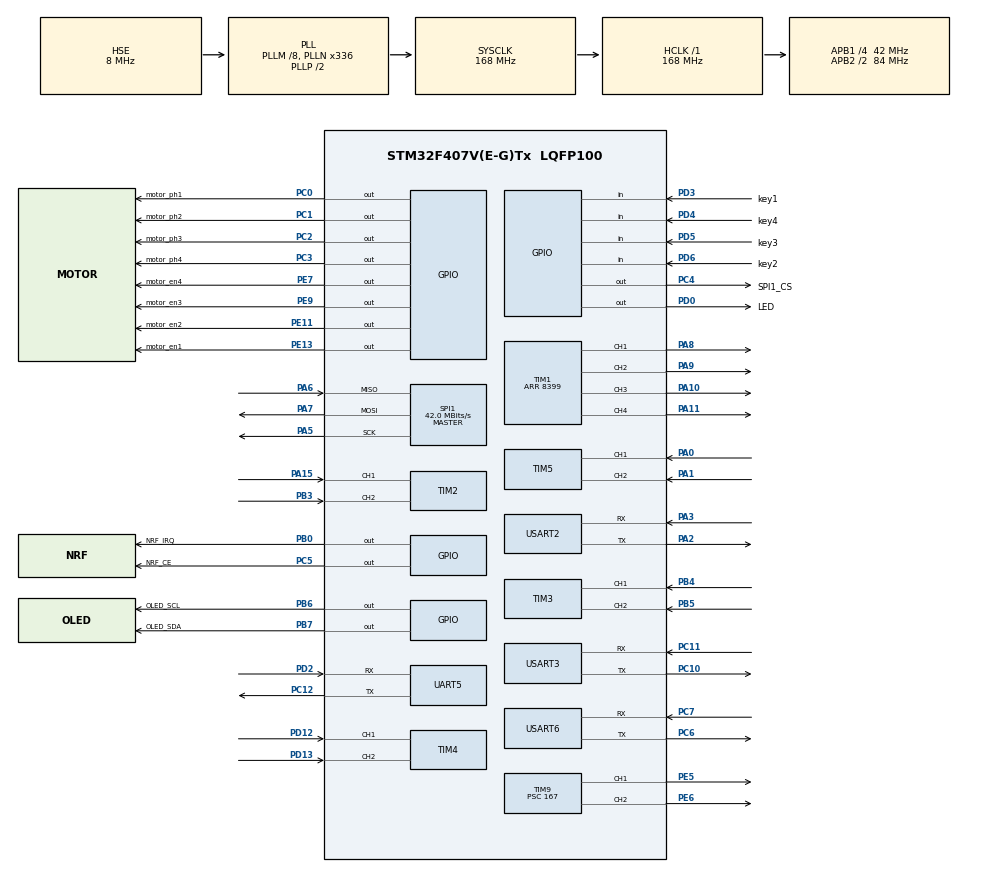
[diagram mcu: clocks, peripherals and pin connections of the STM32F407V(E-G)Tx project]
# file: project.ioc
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Mcu.Family=STM32F4
Mcu.Name=STM32F407V(E-G)Tx
Mcu.Package=LQFP100
NVIC.PriorityGroup=NVIC_PRIORITYGROUP_4
NVIC.UART5_IRQn=true\:0\:0\:false\:false\:true\:true\:true\:true
NVIC.USART2_IRQn=true\:0\:0\:false\:false\:true\:true\:true\:true
NVIC.USART3_IRQn=true\:0\:0\:false\:false\:true\:true\:true\:true
NVIC.USART6_IRQn=true\:0\:0\:false\:false\:true\:true\:true\:true
PA0-WKUP.Signal=S_TIM5_CH1
PA1.Signal=S_TIM5_CH2
PA10.Signal=S_TIM1_CH3
PA11.Signal=S_TIM1_CH4
PA13.Mode=Serial_Wire
PA13.Signal=SYS_JTMS-SWDIO
PA14.Mode=Serial_Wire
PA14.Signal=SYS_JTCK-SWCLK
PA15.Signal=S_TIM2_CH1_ETR
PA2.Mode=Asynchronous
PA2.Signal=USART2_TX
PA3.Mode=Asynchronous
PA3.Signal=USART2_RX
PA5.Mode=Full_Duplex_Master
PA5.Signal=SPI1_SCK
PA6.Mode=Full_Duplex_Master
PA6.Signal=SPI1_MISO
PA7.Mode=Full_Duplex_Master
PA7.Signal=SPI1_MOSI
PA8.Signal=S_TIM1_CH1
PA9.Signal=S_TIM1_CH2
PB0.GPIO_Label=NRF_IRQ
PB0.Signal=GPIO_Output
PB3.Signal=S_TIM2_CH2
PB4.Signal=S_TIM3_CH1
PB5.Signal=S_TIM3_CH2
PB6.GPIO_Label=OLED_SCL
PB6.GPIO_ModeDefaultOutputPP=GPIO_MODE_OUTPUT_PP
PB6.GPIO_PuPd=GPIO_PULLUP
PB6.Signal=GPIO_Output
PB7.GPIO_Label=OLED_SDA
PB7.GPIO_PuPd=GPIO_PULLUP
PB7.PinState=GPIO_PIN_SET
PB7.Signal=GPIO_Output
PC0.GPIO_Label=motor_ph1
PC0.GPIO_Speed=GPIO_SPEED_FREQ_VERY_HIGH
PC0.Signal=GPIO_Output
PC1.GPIO_Label=motor_ph2
PC1.GPIO_Speed=GPIO_SPEED_FREQ_VERY_HIGH
PC1.Signal=GPIO_Output
PC10.Mode=Asynchronous
PC10.Signal=USART3_TX
PC11.Mode=Asynchronous
PC11.Signal=USART3_RX
PC12.Mode=Asynchronous
PC12.Signal=UART5_TX
PC2.GPIO_Label=motor_ph3
PC2.Signal=GPIO_Output
PC3.GPIO_Label=motor_ph4
PC3.Signal=GPIO_Output
PC4.GPIO_Label=SPI1_CS
PC4.Signal=GPIO_Output
PC5.GPIO_Label=NRF_CE
PC5.Signal=GPIO_Output
PC6.Mode=Asynchronous
PC6.Signal=USART6_TX
PC7.Mode=Asynchronous
PC7.Signal=USART6_RX
PD0.GPIO_Label=LED
PD0.Signal=GPIO_Output
PD12.Signal=S_TIM4_CH1
PD13.Signal=S_TIM4_CH2
PD2.Mode=Asynchronous
PD2.Signal=UART5_RX
PD3.GPIO_Label=key1
PD3.Signal=GPIO_Input
PD4.GPIO_Label=key4
PD4.Signal=GPIO_Input
PD5.GPIO_Label=key3
PD5.Signal=GPIO_Input
PD6.GPIO_Label=key2
PD6.Signal=GPIO_Input
PE11.GPIO_Label=motor_en2
PE11.Signal=GPIO_Output
PE13.GPIO_Label=motor_en1
PE13.Signal=GPIO_Output
PE5.Signal=S_TIM9_CH1
PE6.Signal=S_TIM9_CH2
PE7.GPIO_Label=motor_en4
PE7.Signal=GPIO_Output
PE9.GPIO_Label=motor_en3
PE9.Signal=GPIO_Output
PH0-OSC_IN.Mode=HSE-External-Oscillator
PH0-OSC_IN.Signal=RCC_OSC_IN
PH1-OSC_OUT.Mode=HSE-External-Oscillator
PH1-OSC_OUT.Signal=RCC_OSC_OUT
ProjectManager.HeapSize=0x200
ProjectManager.StackSize=0x400
ProjectManager.TargetToolchain=MDK-ARM V5
RCC.48MHZClocksFreq_Value=84000000
RCC.AHBFreq_Value=168000000
RCC.APB1CLKDivider=RCC_HCLK_DIV4
RCC.APB1Freq_Value=42000000
RCC.APB1TimFreq_Value=84000000
RCC.APB2CLKDivider=RCC_HCLK_DIV2
RCC.APB2Freq_Value=84000000
RCC.APB2TimFreq_Value=168000000
RCC.CortexFreq_Value=168000000
RCC.HCLKFreq_Value=168000000
RCC.HSE_VALUE=8000000
RCC.HSI_VALUE=16000000
RCC.LSE_VALUE=32768
RCC.PLLM=8
RCC.PLLN=336
RCC.PLLSourceVirtual=RCC_PLLSOURCE_HSE
RCC.SYSCLKFreq_VALUE=168000000
RCC.SYSCLKSource=RCC_SYSCLKSOURCE_PLLCLK
RCC.VCOOutputFreq_Value=336000000
SH.S_TIM1_CH1.0=TIM1_CH1,PWM Generation1 CH1
SH.S_TIM1_CH2.0=TIM1_CH2,PWM Generation2 CH2
SH.S_TIM1_CH3.0=TIM1_CH3,PWM Generation3 CH3
SH.S_TIM1_CH4.0=TIM1_CH4,PWM Generation4 CH4
SH.S_TIM2_CH1_ETR.0=TIM2_CH1,Encoder_Interface
SH.S_TIM2_CH2.0=TIM2_CH2,Encoder_Interface
SH.S_TIM3_CH1.0=TIM3_CH1,Encoder_Interface
SH.S_TIM3_CH2.0=TIM3_CH2,Encoder_Interface
SH.S_TIM4_CH1.0=TIM4_CH1,Encoder_Interface
SH.S_TIM4_CH2.0=TIM4_CH2,Encoder_Interface
SH.S_TIM5_CH1.0=TIM5_CH1,Encoder_Interface
SH.S_TIM5_CH2.0=TIM5_CH2,Encoder_Interface
SH.S_TIM9_CH1.0=TIM9_CH1,PWM Generation1 CH1
SH.S_TIM9_CH2.0=TIM9_CH2,PWM Generation2 CH2
SPI1.BaudRatePrescaler=SPI_BAUDRATEPRESCALER_2
SPI1.CalculateBaudRate=42.0 MBits/s
SPI1.Direction=SPI_DIRECTION_2LINES
SPI1.Mode=SPI_MODE_MASTER
SPI1.VirtualType=VM_MASTER
TIM1.AutoReloadPreload=TIM_AUTORELOAD_PRELOAD_ENABLE
TIM1.Channel-PWM\ Generation1\ CH1=TIM_CHANNEL_1
TIM1.Channel-PWM\ Generation2\ CH2=TIM_CHANNEL_2
TIM1.Channel-PWM\ Generation3\ CH3=TIM_CHANNEL_3
TIM1.Channel-PWM\ Generation4\ CH4=TIM_CHANNEL_4
TIM1.Period=8399
TIM2.EncoderMode=TIM_ENCODERMODE_TI12
TIM3.EncoderMode=TIM_ENCODERMODE_TI12
TIM4.EncoderMode=TIM_ENCODERMODE_TI12
TIM5.EncoderMode=TIM_ENCODERMODE_TI12
TIM9.Channel-PWM\ Generation1\ CH1=TIM_CHANNEL_1
TIM9.Channel-PWM\ Generation2\ CH2=TIM_CHANNEL_2
TIM9.Period=19999
TIM9.Prescaler=167
UART5.VirtualMode=Asynchronous
USART2.VirtualMode=VM_ASYNC
USART3.VirtualMode=VM_ASYNC
USART6.VirtualMode=VM_ASYNC
VP_TIM1_VS_ClockSourceINT.Mode=Internal
VP_TIM6_VS_ClockSourceINT.Mode=Enable_Timer
VP_TIM9_VS_ClockSourceINT.Mode=Internal
board=custom

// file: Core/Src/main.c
/* USER CODE BEGIN Header */
/**
  ******************************************************************************
  * @file           : main.c
  * @brief          : Main program body
  ******************************************************************************
  * @attention
  *
  * Copyright (c) 2026 STMicroelectronics.
  * All rights reserved.
  *
  * This software is licensed under terms that can be found in the LICENSE file
  * in the root directory of this software component.
  * If no LICENSE file comes with this software, it is provided AS-IS.
  *
  ******************************************************************************
  */
/* USER CODE END Header */
#include "main.h"
#include "scheduler.h"
#include "motor.h"
#include "nrf.h"
#include "led.h"
#include "key.h"
#include "OLED.h"
/* USER CODE BEGIN Includes */
#include "hdz601.h"
#include "encoder.h"
#include "faraway.h"
#include "decode_move.h"
#include "vision_uart6.h"

/* USER CODE END Includes */

SPI_HandleTypeDef hspi1;

TIM_HandleTypeDef htim1;
TIM_HandleTypeDef htim2;
TIM_HandleTypeDef htim3;
TIM_HandleTypeDef htim4;
TIM_HandleTypeDef htim5;
TIM_HandleTypeDef htim6;
TIM_HandleTypeDef htim9;

UART_HandleTypeDef huart5;
UART_HandleTypeDef huart2;
UART_HandleTypeDef huart3;
UART_HandleTypeDef huart6;

void SystemClock_Config(void);
static void MX_GPIO_Init(void);
static void MX_SPI1_Init(void);
static void MX_TIM1_Init(void);
static void MX_TIM2_Init(void);
static void MX_TIM3_Init(void);
static void MX_TIM4_Init(void);
static void MX_TIM5_Init(void);
static void MX_TIM6_Init(void);
static void MX_TIM9_Init(void);
static void MX_UART5_Init(void);
static void MX_USART2_UART_Init(void);
static void MX_USART3_UART_Init(void);
static void MX_USART6_UART_Init(void);

int main(void)
{

    /* MCU Configuration--------------------------------------------------------*/

    /* Reset of all peripherals, Initializes the Flash interface and the Systick. */
    HAL_Init();

    /* Configure the system clock */
    SystemClock_Config();

    /* Initialize all configured peripherals */
    MX_GPIO_Init();
    MX_SPI1_Init();
    MX_TIM1_Init();
    MX_TIM2_Init();
    MX_TIM3_Init();
    MX_TIM4_Init();
    MX_TIM5_Init();
    MX_TIM6_Init();
    MX_TIM9_Init();
    MX_UART5_Init();
    MX_USART2_UART_Init();
    MX_USART3_UART_Init();
    MX_USART6_UART_Init();
    /* USER CODE BEGIN 2 */
    scheduler_init();

    Motor_Init();
    encoder_init();

    hdz601_init();
    scheduler_add_task(hdz601_process, 5U, 1U);

    OLED_Init();
    vision_uart6_init();
    if (!scheduler_add_task(vision_uart6_process, 5U, 0U) ||
        !scheduler_add_task(vision_uart6_oled_task, 50U, 3U)) {
        Error_Handler();
    }

    /* Stationary vision/OLED bring-up: no startup motor speed test. */
    MotorEnable1(0);
    MotorEnable2(0);
    MotorEnable3(0);
    MotorEnable4(0);
    MotorSetSpeed1(0);
    MotorSetSpeed2(0);
    MotorSetSpeed3(0);
    MotorSetSpeed4(0);

    position_encoder_init();
    scheduler_add_task(position_encoder, 20U, 2U);
    scheduler_add_task(motor_process, 20U, 2U);

    if (!faraway_init()) {
        Error_Handler();
    }
    scheduler_add_task(faraway_process, 50U, 2U);
    scheduler_add_task(faraway_report, 50U, 3U);

    /* USER CODE END 2 */

    /* Infinite loop */
    while (1)
    {

        /* USER CODE BEGIN 3 */
        scheduler_run();
        /* USER CODE END 3 */
    }
}

void SystemClock_Config(void)
{
  RCC_OscInitTypeDef RCC_OscInitStruct = {0};
  RCC_ClkInitTypeDef RCC_ClkInitStruct = {0};

  /** Configure the main internal regulator output voltage
  */
  __HAL_RCC_PWR_CLK_ENABLE();
  __HAL_PWR_VOLTAGESCALING_CONFIG(PWR_REGULATOR_VOLTAGE_SCALE1);

  /** Initializes the RCC Oscillators according to the specified parameters
  * in the RCC_OscInitTypeDef structure.
  */
  RCC_OscInitStruct.OscillatorType = RCC_OSCILLATORTYPE_HSE;
  RCC_OscInitStruct.HSEState = RCC_HSE_ON;
  RCC_OscInitStruct.PLL.PLLState = RCC_PLL_ON;
  RCC_OscInitStruct.PLL.PLLSource = RCC_PLLSOURCE_HSE;
  RCC_OscInitStruct.PLL.PLLM = 8;
  RCC_OscInitStruct.PLL.PLLN = 336;
  RCC_OscInitStruct.PLL.PLLP = RCC_PLLP_DIV2;
  RCC_OscInitStruct.PLL.PLLQ = 4;
  if (HAL_RCC_OscConfig(&RCC_OscInitStruct) != HAL_OK)
  {
    Error_Handler();
  }

  /** Initializes the CPU, AHB and APB buses clocks
  */
  RCC_ClkInitStruct.ClockType = RCC_CLOCKTYPE_HCLK|RCC_CLOCKTYPE_SYSCLK
                              |RCC_CLOCKTYPE_PCLK1|RCC_CLOCKTYPE_PCLK2;
  RCC_ClkInitStruct.SYSCLKSource = RCC_SYSCLKSOURCE_PLLCLK;
  RCC_ClkInitStruct.AHBCLKDivider = RCC_SYSCLK_DIV1;
  RCC_ClkInitStruct.APB1CLKDivider = RCC_HCLK_DIV4;
  RCC_ClkInitStruct.APB2CLKDivider = RCC_HCLK_DIV2;

  if (HAL_RCC_ClockConfig(&RCC_ClkInitStruct, FLASH_LATENCY_5) != HAL_OK)
  {
    Error_Handler();
  }
}

static void MX_SPI1_Init(void)
{

  /* SPI1 parameter configuration*/
  hspi1.Instance = SPI1;
  hspi1.Init.Mode = SPI_MODE_MASTER;
  hspi1.Init.Direction = SPI_DIRECTION_2LINES;
  hspi1.Init.DataSize = SPI_DATASIZE_8BIT;
  hspi1.Init.CLKPolarity = SPI_POLARITY_LOW;
  hspi1.Init.CLKPhase = SPI_PHASE_1EDGE;
  hspi1.Init.NSS = SPI_NSS_SOFT;
  hspi1.Init.BaudRatePrescaler = SPI_BAUDRATEPRESCALER_2;
  hspi1.Init.FirstBit = SPI_FIRSTBIT_MSB;
  hspi1.Init.TIMode = SPI_TIMODE_DISABLE;
  hspi1.Init.CRCCalculation = SPI_CRCCALCULATION_DISABLE;
  hspi1.Init.CRCPolynomial = 10;
  if (HAL_SPI_Init(&hspi1) != HAL_OK)
  {
    Error_Handler();
  }

}

static void MX_TIM1_Init(void)
{

  TIM_ClockConfigTypeDef sClockSourceConfig = {0};
  TIM_MasterConfigTypeDef sMasterConfig = {0};
  TIM_OC_InitTypeDef sConfigOC = {0};
  TIM_BreakDeadTimeConfigTypeDef sBreakDeadTimeConfig = {0};

  htim1.Instance = TIM1;
  htim1.Init.Prescaler = 0;
  htim1.Init.CounterMode = TIM_COUNTERMODE_UP;
  htim1.Init.Period = 8399;
  htim1.Init.ClockDivision = TIM_CLOCKDIVISION_DIV1;
  htim1.Init.RepetitionCounter = 0;
  htim1.Init.AutoReloadPreload = TIM_AUTORELOAD_PRELOAD_ENABLE;
  if (HAL_TIM_Base_Init(&htim1) != HAL_OK)
  {
    Error_Handler();
  }
  sClockSourceConfig.ClockSource = TIM_CLOCKSOURCE_INTERNAL;
  if (HAL_TIM_ConfigClockSource(&htim1, &sClockSourceConfig) != HAL_OK)
  {
    Error_Handler();
  }
  if (HAL_TIM_PWM_Init(&htim1) != HAL_OK)
  {
    Error_Handler();
  }
  sMasterConfig.MasterOutputTrigger = TIM_TRGO_RESET;
  sMasterConfig.MasterSlaveMode = TIM_MASTERSLAVEMODE_DISABLE;
  if (HAL_TIMEx_MasterConfigSynchronization(&htim1, &sMasterConfig) != HAL_OK)
  {
    Error_Handler();
  }
  sConfigOC.OCMode = TIM_OCMODE_PWM1;
  sConfigOC.Pulse = 0;
  sConfigOC.OCPolarity = TIM_OCPOLARITY_HIGH;
  sConfigOC.OCNPolarity = TIM_OCNPOLARITY_HIGH;
  sConfigOC.OCFastMode = TIM_OCFAST_DISABLE;
  sConfigOC.OCIdleState = TIM_OCIDLESTATE_RESET;
  sConfigOC.OCNIdleState = TIM_OCNIDLESTATE_RESET;
  if (HAL_TIM_PWM_ConfigChannel(&htim1, &sConfigOC, TIM_CHANNEL_1) != HAL_OK)
  {
    Error_Handler();
  }
  if (HAL_TIM_PWM_ConfigChannel(&htim1, &sConfigOC, TIM_CHANNEL_2) != HAL_OK)
  {
    Error_Handler();
  }
  if (HAL_TIM_PWM_ConfigChannel(&htim1, &sConfigOC, TIM_CHANNEL_3) != HAL_OK)
  {
    Error_Handler();
  }
  if (HAL_TIM_PWM_ConfigChannel(&htim1, &sConfigOC, TIM_CHANNEL_4) != HAL_OK)
  {
    Error_Handler();
  }
  sBreakDeadTimeConfig.OffStateRunMode = TIM_OSSR_DISABLE;
  sBreakDeadTimeConfig.OffStateIDLEMode = TIM_OSSI_DISABLE;
  sBreakDeadTimeConfig.LockLevel = TIM_LOCKLEVEL_OFF;
  sBreakDeadTimeConfig.DeadTime = 0;
  sBreakDeadTimeConfig.BreakState = TIM_BREAK_DISABLE;
  sBreakDeadTimeConfig.BreakPolarity = TIM_BREAKPOLARITY_HIGH;
  sBreakDeadTimeConfig.AutomaticOutput = TIM_AUTOMATICOUTPUT_DISABLE;
  if (HAL_TIMEx_ConfigBreakDeadTime(&htim1, &sBreakDeadTimeConfig) != HAL_OK)
  {
    Error_Handler();
  }
  HAL_TIM_MspPostInit(&htim1);

}

static void MX_TIM2_Init(void)
{

  TIM_Encoder_InitTypeDef sConfig = {0};
  TIM_MasterConfigTypeDef sMasterConfig = {0};

  htim2.Instance = TIM2;
  htim2.Init.Prescaler = 0;
  htim2.Init.CounterMode = TIM_COUNTERMODE_UP;
  htim2.Init.Period = 4294967295;
  htim2.Init.ClockDivision = TIM_CLOCKDIVISION_DIV1;
  htim2.Init.AutoReloadPreload = TIM_AUTORELOAD_PRELOAD_DISABLE;
  sConfig.EncoderMode = TIM_ENCODERMODE_TI12;
  sConfig.IC1Polarity = TIM_ICPOLARITY_RISING;
  sConfig.IC1Selection = TIM_ICSELECTION_DIRECTTI;
  sConfig.IC1Prescaler = TIM_ICPSC_DIV1;
  sConfig.IC1Filter = 0;
  sConfig.IC2Polarity = TIM_ICPOLARITY_RISING;
  sConfig.IC2Selection = TIM_ICSELECTION_DIRECTTI;
  sConfig.IC2Prescaler = TIM_ICPSC_DIV1;
  sConfig.IC2Filter = 0;
  if (HAL_TIM_Encoder_Init(&htim2, &sConfig) != HAL_OK)
  {
    Error_Handler();
  }
  sMasterConfig.MasterOutputTrigger = TIM_TRGO_RESET;
  sMasterConfig.MasterSlaveMode = TIM_MASTERSLAVEMODE_DISABLE;
  if (HAL_TIMEx_MasterConfigSynchronization(&htim2, &sMasterConfig) != HAL_OK)
  {
    Error_Handler();
  }

}

static void MX_TIM3_Init(void)
{

  TIM_Encoder_InitTypeDef sConfig = {0};
  TIM_MasterConfigTypeDef sMasterConfig = {0};

  htim3.Instance = TIM3;
  htim3.Init.Prescaler = 0;
  htim3.Init.CounterMode = TIM_COUNTERMODE_UP;
  htim3.Init.Period = 65535;
  htim3.Init.ClockDivision = TIM_CLOCKDIVISION_DIV1;
  htim3.Init.AutoReloadPreload = TIM_AUTORELOAD_PRELOAD_DISABLE;
  sConfig.EncoderMode = TIM_ENCODERMODE_TI12;
  sConfig.IC1Polarity = TIM_ICPOLARITY_RISING;
  sConfig.IC1Selection = TIM_ICSELECTION_DIRECTTI;
  sConfig.IC1Prescaler = TIM_ICPSC_DIV1;
  sConfig.IC1Filter = 0;
  sConfig.IC2Polarity = TIM_ICPOLARITY_RISING;
  sConfig.IC2Selection = TIM_ICSELECTION_DIRECTTI;
  sConfig.IC2Prescaler = TIM_ICPSC_DIV1;
  sConfig.IC2Filter = 0;
  if (HAL_TIM_Encoder_Init(&htim3, &sConfig) != HAL_OK)
  {
    Error_Handler();
  }
  sMasterConfig.MasterOutputTrigger = TIM_TRGO_RESET;
  sMasterConfig.MasterSlaveMode = TIM_MASTERSLAVEMODE_DISABLE;
  if (HAL_TIMEx_MasterConfigSynchronization(&htim3, &sMasterConfig) != HAL_OK)
  {
    Error_Handler();
  }

}

static void MX_TIM4_Init(void)
{

  TIM_Encoder_InitTypeDef sConfig = {0};
  TIM_MasterConfigTypeDef sMasterConfig = {0};

  htim4.Instance = TIM4;
  htim4.Init.Prescaler = 0;
  htim4.Init.CounterMode = TIM_COUNTERMODE_UP;
  htim4.Init.Period = 65535;
  htim4.Init.ClockDivision = TIM_CLOCKDIVISION_DIV1;
  htim4.Init.AutoReloadPreload = TIM_AUTORELOAD_PRELOAD_DISABLE;
  sConfig.EncoderMode = TIM_ENCODERMODE_TI12;
  sConfig.IC1Polarity = TIM_ICPOLARITY_RISING;
  sConfig.IC1Selection = TIM_ICSELECTION_DIRECTTI;
  sConfig.IC1Prescaler = TIM_ICPSC_DIV1;
  sConfig.IC1Filter = 0;
  sConfig.IC2Polarity = TIM_ICPOLARITY_RISING;
  sConfig.IC2Selection = TIM_ICSELECTION_DIRECTTI;
  sConfig.IC2Prescaler = TIM_ICPSC_DIV1;
  sConfig.IC2Filter = 0;
  if (HAL_TIM_Encoder_Init(&htim4, &sConfig) != HAL_OK)
  {
    Error_Handler();
  }
  sMasterConfig.MasterOutputTrigger = TIM_TRGO_RESET;
  sMasterConfig.MasterSlaveMode = TIM_MASTERSLAVEMODE_DISABLE;
  if (HAL_TIMEx_MasterConfigSynchronization(&htim4, &sMasterConfig) != HAL_OK)
  {
    Error_Handler();
  }

}

static void MX_TIM5_Init(void)
{

  TIM_Encoder_InitTypeDef sConfig = {0};
  TIM_MasterConfigTypeDef sMasterConfig = {0};

  htim5.Instance = TIM5;
  htim5.Init.Prescaler = 0;
  htim5.Init.CounterMode = TIM_COUNTERMODE_UP;
  htim5.Init.Period = 4294967295;
  htim5.Init.ClockDivision = TIM_CLOCKDIVISION_DIV1;
  htim5.Init.AutoReloadPreload = TIM_AUTORELOAD_PRELOAD_DISABLE;
  sConfig.EncoderMode = TIM_ENCODERMODE_TI12;
  sConfig.IC1Polarity = TIM_ICPOLARITY_RISING;
  sConfig.IC1Selection = TIM_ICSELECTION_DIRECTTI;
  sConfig.IC1Prescaler = TIM_ICPSC_DIV1;
  sConfig.IC1Filter = 0;
  sConfig.IC2Polarity = TIM_ICPOLARITY_RISING;
  sConfig.IC2Selection = TIM_ICSELECTION_DIRECTTI;
  sConfig.IC2Prescaler = TIM_ICPSC_DIV1;
  sConfig.IC2Filter = 0;
  if (HAL_TIM_Encoder_Init(&htim5, &sConfig) != HAL_OK)
  {
    Error_Handler();
  }
  sMasterConfig.MasterOutputTrigger = TIM_TRGO_RESET;
  sMasterConfig.MasterSlaveMode = TIM_MASTERSLAVEMODE_DISABLE;
  if (HAL_TIMEx_MasterConfigSynchronization(&htim5, &sMasterConfig) != HAL_OK)
  {
    Error_Handler();
  }

}

static void MX_TIM6_Init(void)
{

  TIM_MasterConfigTypeDef sMasterConfig = {0};

  htim6.Instance = TIM6;
  htim6.Init.Prescaler = 0;
  htim6.Init.CounterMode = TIM_COUNTERMODE_UP;
  htim6.Init.Period = 65535;
  htim6.Init.AutoReloadPreload = TIM_AUTORELOAD_PRELOAD_DISABLE;
  if (HAL_TIM_Base_Init(&htim6) != HAL_OK)
  {
    Error_Handler();
  }
  sMasterConfig.MasterOutputTrigger = TIM_TRGO_RESET;
  sMasterConfig.MasterSlaveMode = TIM_MASTERSLAVEMODE_DISABLE;
  if (HAL_TIMEx_MasterConfigSynchronization(&htim6, &sMasterConfig) != HAL_OK)
  {
    Error_Handler();
  }

}

static void MX_TIM9_Init(void)
{

  TIM_ClockConfigTypeDef sClockSourceConfig = {0};
  TIM_OC_InitTypeDef sConfigOC = {0};

  htim9.Instance = TIM9;
  htim9.Init.Prescaler = 167;
  htim9.Init.CounterMode = TIM_COUNTERMODE_UP;
  htim9.Init.Period = 19999;
  htim9.Init.ClockDivision = TIM_CLOCKDIVISION_DIV1;
  htim9.Init.AutoReloadPreload = TIM_AUTORELOAD_PRELOAD_DISABLE;
  if (HAL_TIM_Base_Init(&htim9) != HAL_OK)
  {
    Error_Handler();
  }
  sClockSourceConfig.ClockSource = TIM_CLOCKSOURCE_INTERNAL;
  if (HAL_TIM_ConfigClockSource(&htim9, &sClockSourceConfig) != HAL_OK)
  {
    Error_Handler();
  }
  if (HAL_TIM_PWM_Init(&htim9) != HAL_OK)
  {
    Error_Handler();
  }
  sConfigOC.OCMode = TIM_OCMODE_PWM1;
  sConfigOC.Pulse = 0;
  sConfigOC.OCPolarity = TIM_OCPOLARITY_HIGH;
  sConfigOC.OCFastMode = TIM_OCFAST_DISABLE;
  if (HAL_TIM_PWM_ConfigChannel(&htim9, &sConfigOC, TIM_CHANNEL_1) != HAL_OK)
  {
    Error_Handler();
  }
  if (HAL_TIM_PWM_ConfigChannel(&htim9, &sConfigOC, TIM_CHANNEL_2) != HAL_OK)
  {
    Error_Handler();
  }
  HAL_TIM_MspPostInit(&htim9);

}

static void MX_UART5_Init(void)
{

  huart5.Instance = UART5;
  huart5.Init.BaudRate = 115200;
  huart5.Init.WordLength = UART_WORDLENGTH_8B;
  huart5.Init.StopBits = UART_STOPBITS_1;
  huart5.Init.Parity = UART_PARITY_NONE;
  huart5.Init.Mode = UART_MODE_TX_RX;
  huart5.Init.HwFlowCtl = UART_HWCONTROL_NONE;
  huart5.Init.OverSampling = UART_OVERSAMPLING_16;
  if (HAL_UART_Init(&huart5) != HAL_OK)
  {
    Error_Handler();
  }

}

static void MX_USART2_UART_Init(void)
{

  huart2.Instance = USART2;
  huart2.Init.BaudRate = 115200;
  huart2.Init.WordLength = UART_WORDLENGTH_8B;
  huart2.Init.StopBits = UART_STOPBITS_1;
  huart2.Init.Parity = UART_PARITY_NONE;
  huart2.Init.Mode = UART_MODE_TX_RX;
  huart2.Init.HwFlowCtl = UART_HWCONTROL_NONE;
  huart2.Init.OverSampling = UART_OVERSAMPLING_16;
  if (HAL_UART_Init(&huart2) != HAL_OK)
  {
    Error_Handler();
  }

}

static void MX_USART3_UART_Init(void)
{

  huart3.Instance = USART3;
  huart3.Init.BaudRate = 115200;
  huart3.Init.WordLength = UART_WORDLENGTH_8B;
  huart3.Init.StopBits = UART_STOPBITS_1;
  huart3.Init.Parity = UART_PARITY_NONE;
  huart3.Init.Mode = UART_MODE_TX_RX;
  huart3.Init.HwFlowCtl = UART_HWCONTROL_NONE;
  huart3.Init.OverSampling = UART_OVERSAMPLING_16;
  if (HAL_UART_Init(&huart3) != HAL_OK)
  {
    Error_Handler();
  }

}

static void MX_USART6_UART_Init(void)
{

  huart6.Instance = USART6;
  huart6.Init.BaudRate = 115200;
  huart6.Init.WordLength = UART_WORDLENGTH_8B;
  huart6.Init.StopBits = UART_STOPBITS_1;
  huart6.Init.Parity = UART_PARITY_NONE;
  huart6.Init.Mode = UART_MODE_TX_RX;
  huart6.Init.HwFlowCtl = UART_HWCONTROL_NONE;
  huart6.Init.OverSampling = UART_OVERSAMPLING_16;
  if (HAL_UART_Init(&huart6) != HAL_OK)
  {
    Error_Handler();
  }

}

static void MX_GPIO_Init(void)
{
  GPIO_InitTypeDef GPIO_InitStruct = {0};

  /* GPIO Ports Clock Enable */
  __HAL_RCC_GPIOE_CLK_ENABLE();
  __HAL_RCC_GPIOH_CLK_ENABLE();
  __HAL_RCC_GPIOC_CLK_ENABLE();
  __HAL_RCC_GPIOA_CLK_ENABLE();
  __HAL_RCC_GPIOB_CLK_ENABLE();
  __HAL_RCC_GPIOD_CLK_ENABLE();

  /*Configure GPIO pin Output Level */
  HAL_GPIO_WritePin(GPIOC, motor1_Pin|motor2_Pin|motor3_Pin|motor4_Pin
                          |SPI1_CS_Pin|NRF_CE_Pin, GPIO_PIN_RESET);

  /*Configure GPIO pin Output Level */
  HAL_GPIO_WritePin(GPIOB, NRF_IRQ_Pin|OLED_SCL_Pin, GPIO_PIN_RESET);

  /*Configure GPIO pin Output Level */
  HAL_GPIO_WritePin(GPIOE, motor4_En_Pin|motor3_En_Pin|motor2_En_Pin|motor1_En_Pin, GPIO_PIN_RESET);

  /*Configure GPIO pin Output Level */
  HAL_GPIO_WritePin(LED_Port, LED_Pin, GPIO_PIN_RESET);

  /*Configure GPIO pin Output Level */
  HAL_GPIO_WritePin(OLED_SDA_GPIO_Port, OLED_SDA_Pin, GPIO_PIN_SET);

  /*Configure GPIO pins : motor1_Pin motor2_Pin */
  GPIO_InitStruct.Pin = motor1_Pin|motor2_Pin;
  GPIO_InitStruct.Mode = GPIO_MODE_OUTPUT_PP;
  GPIO_InitStruct.Pull = GPIO_NOPULL;
  GPIO_InitStruct.Speed = GPIO_SPEED_FREQ_VERY_HIGH;
  HAL_GPIO_Init(GPIOC, &GPIO_InitStruct);

  /*Configure GPIO pins : motor3_Pin motor4_Pin SPI1_CS_Pin NRF_CE_Pin */
  GPIO_InitStruct.Pin = motor3_Pin|motor4_Pin|SPI1_CS_Pin|NRF_CE_Pin;
  GPIO_InitStruct.Mode = GPIO_MODE_OUTPUT_PP;
  GPIO_InitStruct.Pull = GPIO_NOPULL;
  GPIO_InitStruct.Speed = GPIO_SPEED_FREQ_LOW;
  HAL_GPIO_Init(GPIOC, &GPIO_InitStruct);

  /*Configure GPIO pin : NRF_IRQ_Pin */
  GPIO_InitStruct.Pin = NRF_IRQ_Pin;
  GPIO_InitStruct.Mode = GPIO_MODE_OUTPUT_PP;
  GPIO_InitStruct.Pull = GPIO_NOPULL;
  GPIO_InitStruct.Speed = GPIO_SPEED_FREQ_LOW;
  HAL_GPIO_Init(NRF_IRQ_GPIO_Port, &GPIO_InitStruct);

  /*Configure GPIO pins : motor4_En_Pin motor3_En_Pin motor2_En_Pin motor1_En_Pin */
  GPIO_InitStruct.Pin = motor4_En_Pin|motor3_En_Pin|motor2_En_Pin|motor1_En_Pin;
  GPIO_InitStruct.Mode = GPIO_MODE_OUTPUT_PP;
  GPIO_InitStruct.Pull = GPIO_NOPULL;
  GPIO_InitStruct.Speed = GPIO_SPEED_FREQ_LOW;
  HAL_GPIO_Init(GPIOE, &GPIO_InitStruct);

  /*Configure GPIO pin : LED_Pin */
  GPIO_InitStruct.Pin = LED_Pin;
  GPIO_InitStruct.Mode = GPIO_MODE_OUTPUT_PP;
  GPIO_InitStruct.Pull = GPIO_NOPULL;
  GPIO_InitStruct.Speed = GPIO_SPEED_FREQ_LOW;
  HAL_GPIO_Init(LED_Port, &GPIO_InitStruct);

  /*Configure GPIO pins : key1_Pin key4_Pin key3_Pin key2_Pin */
  GPIO_InitStruct.Pin = key1_Pin|key4_Pin|key3_Pin|key2_Pin;
  GPIO_InitStruct.Mode = GPIO_MODE_INPUT;
  GPIO_InitStruct.Pull = GPIO_NOPULL;
  HAL_GPIO_Init(GPIOD, &GPIO_InitStruct);

  /*Configure GPIO pins : OLED_SCL_Pin OLED_SDA_Pin */
  GPIO_InitStruct.Pin = OLED_SCL_Pin|OLED_SDA_Pin;
  GPIO_InitStruct.Mode = GPIO_MODE_OUTPUT_PP;
  GPIO_InitStruct.Pull = GPIO_PULLUP;
  GPIO_InitStruct.Speed = GPIO_SPEED_FREQ_LOW;
  HAL_GPIO_Init(GPIOB, &GPIO_InitStruct);

}

void Error_Handler(void)
{
  __disable_irq();
  while (1)
  {
  }
}
